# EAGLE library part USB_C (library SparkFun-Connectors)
USB Type C 16Pin Connector Super Speed pins not available on the 16-pin purely SMD connector so this part is best for USB 2.0 implementations. D1 and D2 are tied together enabling D+/- no matter which way the cable is plugged into the connector. The two channel configuration pins (CC1/2) are exposed. These are normally connected to ground via 5.1k resistors but can be reconfigured for high current/high power applications.

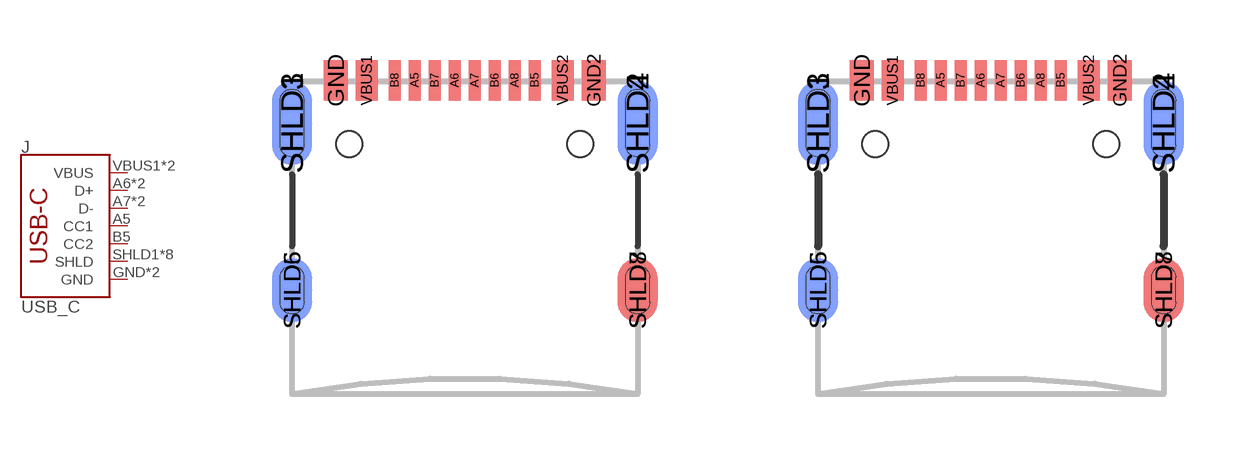
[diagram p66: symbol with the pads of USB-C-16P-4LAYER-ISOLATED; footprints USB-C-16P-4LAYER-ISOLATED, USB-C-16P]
Designator prefix J

## USB_C4-LAYER-ISOLATED (PROD_ID: CONN-14122; VALUE: USB Female Type C Connector)  [USB-C-16P-4LAYER-ISOLATED]
A5  CC1
A6  D+
A7  D-
B5  CC2
B6  D+
B7  D-
GND  GND
GND2  GND
SHLD1  SHLD
SHLD2  SHLD
SHLD3  SHLD
SHLD4  SHLD
SHLD5  SHLD
SHLD6  SHLD
SHLD7  SHLD
SHLD8  SHLD
VBUS1  VBUS
VBUS2  VBUS

## USB_C2-LAYER (PROD_ID: CONN-14122)  [USB-C-16P]
Pads as for USB-C-16P-4LAYER-ISOLATED

## Footprint USB-C-16P-4LAYER-ISOLATED (pad centres in mm)
smd 0.3 x 1.016: A5 -1.25,0.154; A6 -0.25,0.154; A7 0.25,0.154; A8 1.25,0.154; B5 1.75,0.154; B6 0.75,0.154; B7 -0.75,0.154; B8 -1.75,0.154
smd 0.6 x 1.016: GND -3.225,0.154; GND2 3.225,0.154
smd 1 x 2.1: SHLD1 -4.32,-0.915; SHLD2 4.32,-0.915
smd 1 x 2.1 bottom: SHLD3 -4.32,-0.915; SHLD4 4.32,-0.915
smd 1 x 1.6: SHLD5 -4.32,-5.095; SHLD8 4.32,-5.095
smd 1 x 1.6 bottom: SHLD6 -4.32,-5.095; SHLD7 4.32,-5.095
smd 0.55 x 1.016: VBUS1 -2.45,0.154; VBUS2 2.45,0.154
hole 0.65 at -2.89,-1.445
hole 0.65 at 2.89,-1.445

## Footprint USB-C-16P (pad centres in mm)
smd 0.3 x 1.016: A5 -1.25,0.154; A6 -0.25,0.154; A7 0.25,0.154; A8 1.25,0.154; B5 1.75,0.154; B6 0.75,0.154; B7 -0.75,0.154; B8 -1.75,0.154
smd 0.6 x 1.016: GND -3.225,0.154; GND2 3.225,0.154
smd 1 x 2.1: SHLD1 -4.32,-0.915; SHLD2 4.32,-0.915
smd 1 x 2.1 bottom: SHLD3 -4.32,-0.915; SHLD4 4.32,-0.915
smd 1 x 1.6: SHLD5 -4.32,-5.095; SHLD8 4.32,-5.095
smd 1 x 1.6 bottom: SHLD6 -4.32,-5.095; SHLD7 4.32,-5.095
smd 0.55 x 1.016: VBUS1 -2.45,0.154; VBUS2 2.45,0.154
hole 0.65 at -2.89,-1.445
hole 0.65 at 2.89,-1.445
